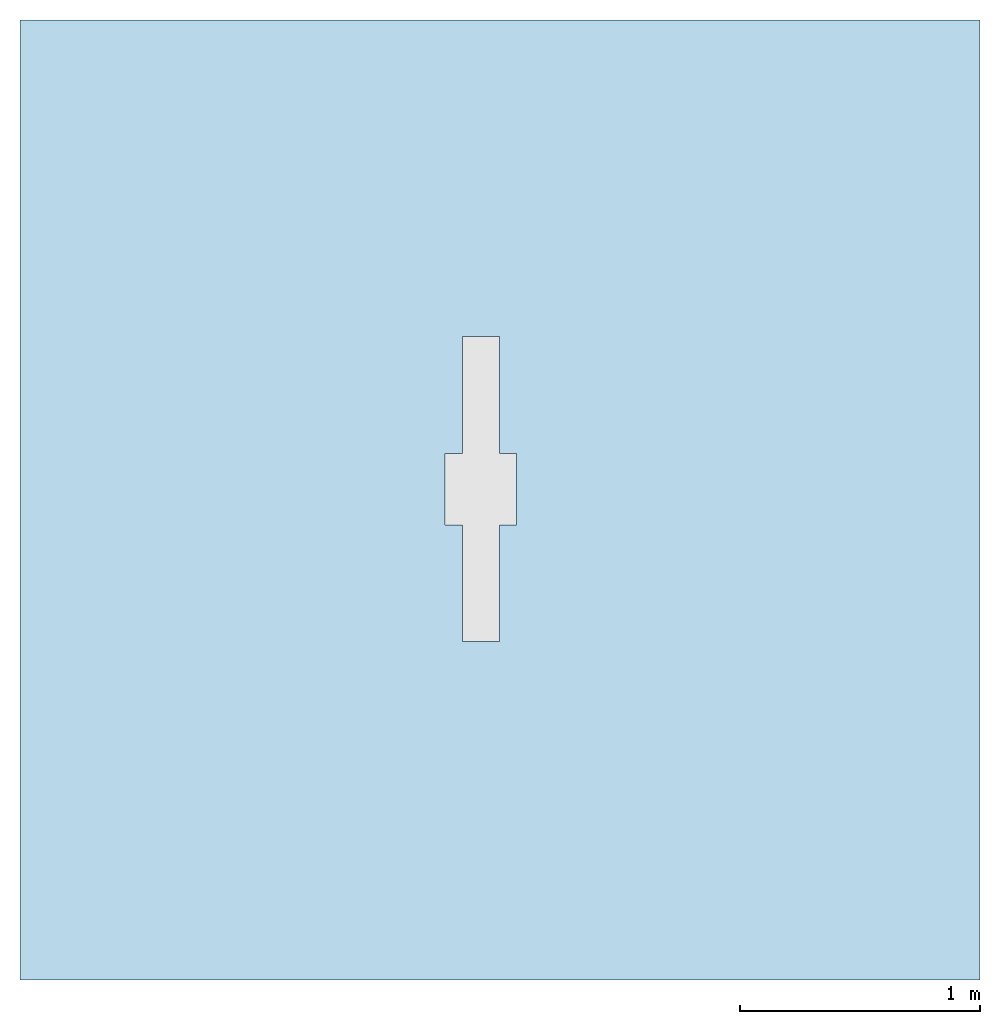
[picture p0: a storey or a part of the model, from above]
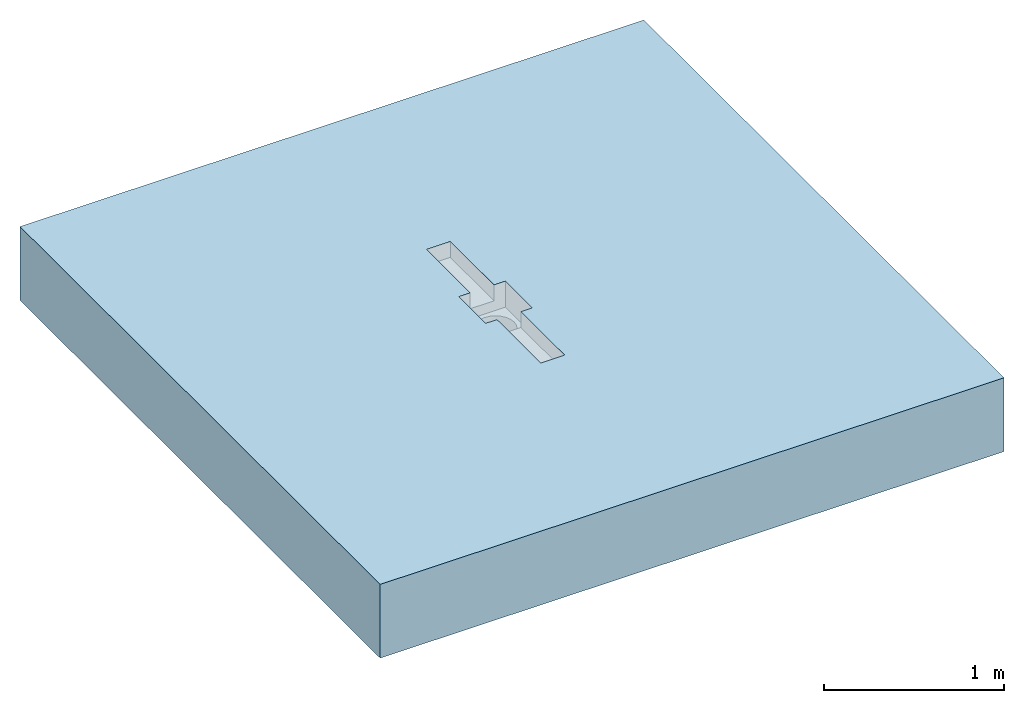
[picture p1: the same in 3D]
Properties of the parts of a building model (IFC2X3)

# File
Description: ViewDefinition [CoordinationView]
File name: 105379 - Two Way Gully Top - 1270 mm LG - Invert Depth 95mm.ifc
Time: 2014-03-19T12:25:05
Written by: Autodesk Revit 2013
Made in: 20120221_2030(x64)

# IfcProject, Project Number
LongName: Project Name; Phase: Project Status

# IfcSite, Default
RefLatitude: 42, 21, 30, 344238; RefLongitude: -71, -3, -35, -194702; RefElevation: 0 mm

# IfcBuilding
Pset_BuildingCommon - NumberOfStoreys: 1
Other - Project Status: Project Status; Client Name: Owner; Project Issue Date: Issue Date; Project Address: ## Street City, State Zip; Project Number: Project Number; Project Name: Project Name

# IfcBuildingStorey, Level 1
LongName: Level 1; Elevation: 0 mm
Constraints - Elevation Base: 0; Elevation: 0 mm
Graphics - Symbol at End 2 Default: yes; Symbol: M_Level Head - Circle: M_Level Head - Circle; Color: 0; Line Pattern: Center; Line Weight: 1; Symbol at End 1 Default: no
Identity Data - Building Story: yes; Name: Level 1; Structural: no
Dimensions - Computation Height: 0 mm

# IfcFlowTerminal: 105379 - Two Way Gully Top - 1270 mm LG - Invert Depth 95mm, ACO BD Modular 125 One and Two Way Gully Units:105379 - Two Way Gully Top - 1270 mm LG - Invert Depth 95mm:105379 - Two Way Gully Top - 1270 mm LG - Invert Depth 95mm:204969
In: Level 1
Material: Rubber, Nitrile, Stainless Steel AISI 304, Polystyrene, High Impact
Construction - Grating Two Way: yes; Detail 95mm: yes; Grating One Way: yes; Detail 125mm: no; Detail 65mm: no; 105519 - Slotted Locked - Stainless Steel 304 - 500mm long: no; 105848 - Slip Resistant Intercept Locked - Stainless Steel 304 - 500mm long: no; 105505 - Perforated Locked - Stainless Steel 304 - 500mm long: no; 105846 - Slip Resistant Intercept - Stainless Steel 304 - 500mm long: no; 408067_Telescopic_Vertical Outlet Ø_160mm: no; 96819 - Grating - Heal Safe - Stainless Steel 304 - 500mm long: no; 408045 - Plain Ladder - Stainless Steel 304 - 268 x 268mm: no; End Plate Invert 1: no; 105842 - Slip Resistant Quadrato - Stainless Steel 304 - 500mm long: no; 15704 - Composite - Black Composite - 500mm long: no; 408041 - Slip Resistant Arla - Stainless Steel 304 - 268 x 268mm: no; 408220_Outlet Foul Air Trap: yes; 408039 - Slot Cover - Stainless Steel 304 - 268 x 268mm: no; 408223_Horizontal Outlet Gully Silt Basket: no; 105844 - Slip Resistant Quadrato Locked - Stainless Steel 304 - 500mm long: no; 26270_PVC Infill: yes; 21720 - Grating - Plain Mesh - Stainless Steel 304 - 500mm long: no; 105539 - Intercept - Stainless Steel 304 - 500mm long: no; 105530 - Quadrato - Stainless Steel 304 - 500mm long: no; 408037 - Slip Resistant Ladder - Stainless Steel 304 - 268 x 268mm: no; 408063_Telescopic_Vertical Outlet Ø_110mm: no; 408035 - Slip Resistant Mesh - Stainless Steel 304 - 268 x 268mm: no; 10735 - Composite - White Composite - 500mm long: no; 21710 - Grating - Slip Resistant Mesh - Stainless Steel 304 - 500mm long: no; 21910 - Grating - Slip Resistant Mesh - Stainless Steel 304 - 500mm long: no; 408061_Telescopic_Vertical Outlet Ø_110mm: yes; 21740 - Ladder - Stainless Steel 304 - 500mm long: no; 21920 - Grating - Plain Mesh - Stainless Steel 304 - 500mm long: no; 408065_Telescopic_Vertical Outlet Ø_110mm: no; 408085_Telescopic_Horizontal Outlet Ø_110mm: no; 105521 - Slotted Locked - Stainless Steel 304 - 500mm long: no; 49061 & 49062_Vinyl Seal: no; 408042 - Slip Resistant Multi Slot - Stainless Steel 304 - 268 x 268mm: no; 408040 - Heal Safe - Stainless Steel 304 - 268 x 268mm: no; 402072 - Grating - Heal Safe Locked - Stainless Steel 304 - 500mm long: no; 105537 - Intercept Locked - Stainless Steel 304 - 500mm long: no; 408089_Telescopic_Horizontal Outlet Ø_110mm: no; 105528 - Quadrato Locked - Stainless Steel 304 - 500mm long: no; Min & Max Table for Horizontal Gully Outlet: no; 408071_Telescopic_Vertical Outlet Ø_160mm: no; 408038 - Ladder - Stainless Steel 304 - 268 x 268mm: no; 408036 - Quadrato - Stainless Steel 304 - 268 x 268mm: no; Min & Max Table for Vertical Gully Outlet: no; End Plate Invert 2: no; 408222_Verical Outlet Gully Silt Basket: yes; 408069_Telescopic_Vertical Outlet Ø_160mm: no; 21790 - Plastic - White Plastic - 500mm long: no; 408034 - Plain Mesh - Stainless Steel 304 - 268 x 268mm: no; 408087_Telescopic_Horizontal Outlet Ø_110mm: no
Identity Data - Mark: 2; Watermarked With: BIM Manager Premium Suite.; E-mail Sales: abdcommercial@aco.co.uk; Fax: +44 (0)1462 851490; Watermarked By: www.acobd.com; Website: www.acobd.com; E-mail Technical: abdtechnical@aco.co.uk; Watermark2: This file is water marked and users are prohibited to reproduce, adapt, distribute this information.; Manufacturer: ACO Building Drainage; Telephone: +44 (0)1462 816666; Watermark1: This file is the property of ACO Technologies PLC.; Address: ACO Business Centre, Caxton Road, Bedford, MK41 0LF
Dimensions - Vertical Gully Outlet Radius: 55 mm; Horizontal Gully Void Height Start: -1 mm; Horizontal Gully Outlet Radius: 0 mm; Vertical Gully Void Height Start: -18.5 mm; Vertical Gully Void Height End: -290.5 mm; Horizontal Gully Void Height End: 1 mm; Silt Basket Height: 50 mm; Gully Floor Void Radius: 120 mm; Channel to Gully top cutter End: -149 mm; Gully Height from Floor: 139 mm; Two Way PVC In Filll Start: -498 mm; Gully Top Floor Void End: 176.25 mm; Depth: 74 mm; Grating Height: 21 mm; Channel Floor Void End: 1270 mm; Channel Floor Void Height: 107.8 mm; PVC 1 or 2 way: 83.5 mm; Total Height: 107.8 mm
Mechanical - System Classification: Sanitary
Other - 408061: 0 mm; 408071: 400 mm; Silt Basket: yes; Neoprene Gasket: 1; Rigid PVC Extrusion (49061): 0 mm; 408067: 400 mm; PVC Infill Two Way: yes; 408089: 400 mm; 408063: 400 mm; 408087: 400 mm; 408069: 400 mm; PVC Infill (26270): 2830 mm; 408065: 400 mm; 408085: 400 mm; Flexible PVC Seal (49062): 0 mm; One Way Detail 125mm: no; Two Way Channel: yes; One Way Detail 65mm: no; One Way Detail 95mm: yes; Two Way Detail 65mm: no; One Way Channel: yes; Two Way Detail 95mm: yes; Two Way Detail 125mm: no
Constraints - Level: Level: Level 1
Phasing - Phase Created: New Construction
General - Weight (Kg): 7.6; Product Description: ACO Modular 125 Two Way Gully Top; Price: POA - contact ACO; Seal Recyclable: Fully recyclable; Seal Recycled Material Content: 0%; NBS Specification: NBS Section Q10 Kerbs/edgings/channels/paving accessories, Clause 180 Drainage Channel Systems; Dimensions (LxWxH): 1270 x 153 x 65; Channel Recyclable: Fully recyclable; Product Code: 105379; Seal Material: Neoprene; Seal Colour: Black; Channel Colour: Mid Grey; Load Class: A15 - C250; Product Type: Stainless Steel Channel Drainage System; Product Standard: BS EN 1433:2002, CE marked; Product Range: ACO Modular 125; Channel Recycled Material Content: 60-70%; Installation guidelines: X:\Electronic Literature\ABD Electronic Literature\Standard Stainless Steel and Galvanised Steel Channels\ACO Modular 125\ACO Modular 125.pdf; Channel Material: Stainless Steel Grade 304; Maintenance guidelines: X:\Electronic Literature\ABD Electronic Literature\Standard Stainless Steel and Galvanised Steel Channels\ACO Modular 125\ACO Modular 125.pdf
Model Properties - Grating Product Code 408035: Load Class L15 - Slip Resistant Mesh - Stainless Steel 304 - 268 x 268 mm - 2.1kg; Grating Product Code 96819: Load Class B125 - Heal Safe - Stainless Steel 304 - 500mm long - 2.0kg; Grating Product Code 21920: Load Class C250 - Plain Mesh - Stainless Steel 304 - 500mm long - 2.2kg; Grating Product Code 408037: Load Class M125 - Slip Resistant Ladder - Stainless Steel 304 - 268 x 268 mm - 4.3kg; Product Code 408225: Friction Ring Installation Set - Nitrile - 0.09kg; Grating Product Code 105521: Load Class C250 - Slotted Locked - Stainless Steel 304 - 500mm long - 2.3kg; Grating Product Code 408034: Load Class L15 - Plain Mesh - Stainless Steel 304 - 268 x 268 mm - 2.1kg; Grating Product Code 402072: Load Class B125 - Heal Safe Locked - Stainless Steel 304 - 500mm long - 2.0kg; Grating Product Code 105537: Load Class A15 - Intercept Locked - Stainless Steel 304 - 500mm long - 1.8kg; Grating Product Code 105505: Load Class C250 - Perforated Locked - Stainless Steel 304 - 500mm long - 1.8kg; Gully Product Code 408067: Telescopic - 160mm Ø Vertical Outlet - Stainless Steel 304 - Location Flange - Flow Rate 5.0 to 6.3 l/s - 3.2kg; Grating Product Code 105842: Load Class A15 - Slip Resistant Quadrato - Stainless Steel 304 - 500mm long - 1.6kg; Gully Product Code 408085: Telescopic - 110mm Ø Horizontal Outlet - Stainless Steel 304 - Location Flange - Flow Rate 4.4 to 5.5 l/s - 2.2kg; Grating Product Code 408042: Load Class L15 - Slip Resistant Multi Slot - Stainless Steel 304 - 268 x 268 mm - 2.0kg; Gully Product Code 408087: Telescopic - 110mm Ø Horizontal Outlet - Stainless Steel 304 - Adhesive Bonding Flange - Flow Rate 4.4 to 5.5 l/s - 4.2kg; Grating Product Code 21740: Load Class C250 - Ladder - Stainless Steel 304 - 500mm long - 2.0kg; Grating Product Code 21720: Load Class A15 - Plain Mesh - Stainless Steel 304 - 500mm long - 1.6kg; Product Code 408221: Foul Air Trap Support Ring - Nitrile - 0.2kg; Grating Product Code 408038: Load Class M125 - Plain Ladder - Stainless Steel 304 - 268 x 268 mm - 4.3kg; Grating Product Code 408045: Load Class C250 - Plain Ladder - Stainless Steel 304 - 268 x 268 mm - 6.2kg; Grating Product Code 21790: Load Class A15 - Plastic - White Plastic - 500mm long - 0.6kg; Grating Product Code 21910: Load Class C250 - Slip Resistant Mesh - Stainless Steel 304 - 500mm long - 2.2kg; End Plate Product Code 105103: End Plate Stainless Steel 304 for Invert Depth - 95mm - 0.24Kg; Grating Product Code 15704: Load Class C250 - Composite - Black Composite - 500mm long - 1.2kg; Grating Product Code 408036: Load Class L15 - Quadrato - Stainless Steel 304 - 268 x 268 mm - 1.8kg; Gully Product Code 408061: Telescopic - 110mm Ø Vertical Outlet - Stainless Steel 304 - Location Flange - Flow Rate 5.0 to 6.3 l/s - 3.2kg; End Plate Product Code 105105: N/A; Gully Product Code 408063: Telescopic - 110mm Ø Vertical Outlet - Stainless Steel 304 - Adhesive Bonding Flange - Flow Rate 5.0 to 6.3 l/s - 4.4kg; Grating Product Code 105530: Load Class A15 - Quadrato - Stainless Steel 304 - 500mm long - 1.6kg; Grating Product Code 105848: Load Class A15 - Slip Resistant Intercept Locked - Stainless Steel 304 - 500mm long - 1.8kg; Product Code 408223: Horizontal Outlet Gully - Silt Basket - 0.7 litre capacity - Stainless Steel 304 - 0.6kg; Grating Product Code 105528: Load Class A15 - Quadrato Locked - Stainless Steel 304 - 500mm long - 1.6kg; End Plate Product Code 105101: N/A; Gully Product Code 408065: Telescopic - 110mm Ø Vertical Outlet - Stainless Steel 304 - Mechanical Clamping Flange - Flow Rate 5.0 to 6.3 l/s - 5.5kg; Grating Product Code 105846: Load Class A15 - Slip Resistant Intercept - Stainless Steel 304 - 500mm long - 1.8kg; Grating Product Code 105539: Load Class A15 - Intercept - Stainless Steel 304 - 500mm long - 1.8kg; Grating Product Code 105519: Load Class A15 - Slotted Locked - Stainless Steel 304 - 500mm long - 1.0kg; Gully Product Code 408069: Telescopic - 160mm Ø Vertical Outlet - Stainless Steel 304 - Adhesive Bonding Flange - Flow Rate 5.0 to 6.3 l/s - 4.4kg; Product Code 408222: Vertical Outlet Gully - Silt Basket - 1.4 litre capacity - Stainless Steel 304 - 0.7kg; Grating Product Code 408039: Load Class M125 - Slot Cover - Stainless Steel 304 - 268 x 268 mm - 6.0kg; Grating Product Code 21710: Load Class A15 - Slip Resistant Mesh - Stainless Steel 304 - 500mm long - 1.6kg; Gully Product Code 408071: Telescopic - 160mm Ø Vertical Outlet - Stainless Steel 304 - Mechanical Clamping Flange - Flow Rate 5.0 to 6.3 l/s - 5.5kg; Grating Product Code 408041: Load Class L15 - Slip Resistant Arla - Stainless Steel 304 - 268 x 268 mm - 1.8kg; Grating Product Code 105844: Load Class A15 - Slip Resistant Quadrato Locked - Stainless Steel 304 - 500mm long - 1.6kg; Product Code 408220: Outlet Foul Air Trap - Stainless Steel 304 - 1.2kg; Gully Product Code 408089: Telescopic - 110mm Ø Horizontal Outlet - Stainless Steel 304 - Mechanical Clamping Flange - Flow Rate 4.4 to 5.5 l/s - 4.4kg; Grating Product Code 10735: Load Class C250 - Composite - White Composite - 500mm long - 1.2kg; Grating Product Code 408040: Load Class L15 - Heal Safe - Stainless Steel 304 - 268 x 268 mm - 2.4kg

# IfcOpeningElement: Recess
In: Level 1
Dimensions - Volume: 7957820185 mm3; Area: 16000000 mm2; Perimeter: 16000 mm; Thickness: 500 mm
Constraints - Room Bounding: yes; Level: Level: Level 1; Height Offset From Level: 0 mm; Related to Mass: no
Phasing - Phase Created: New Construction
Structural - Structural: no; Enable Analytical Model: no
Analytical Properties - Thermal Resistance (R): 0.478011; Thermal mass: 755550; Absorptance: 0.1; Heat Transfer Coefficient (U): 2.092; Roughness: 1
Construction - Default Thickness: 500 mm; Function: 0
Graphics - Coarse Scale Fill Color: 0
Materials and Finishes - Structural Material: Concrete, Broom Finish

# IfcSlab: Floor:Generic Floor - 500mm, Floor:Generic Floor - 500mm:193825
In: Level 1
PredefinedType: FLOOR; Material: Concrete, Broom Finish 500 mm
Dimensions - Volume: 7957820185 mm3; Area: 16000000 mm2; Perimeter: 16000 mm; Thickness: 500 mm
Constraints - Room Bounding: yes; Level: Level: Level 1; Height Offset From Level: 0 mm; Related to Mass: no
Phasing - Phase Created: New Construction
Structural - Structural: no; Enable Analytical Model: no
Pset_SlabCommon - Reference: Generic Floor - 500mm; IsExternal: no; LoadBearing: yes
Analytical Properties - Thermal Resistance (R): 0.478011; Thermal mass: 755550; Absorptance: 0.1; Heat Transfer Coefficient (U): 2.092; Roughness: 1
Construction - Default Thickness: 500 mm; Function: 0
Graphics - Coarse Scale Fill Color: 0
Materials and Finishes - Structural Material: Concrete, Broom Finish
